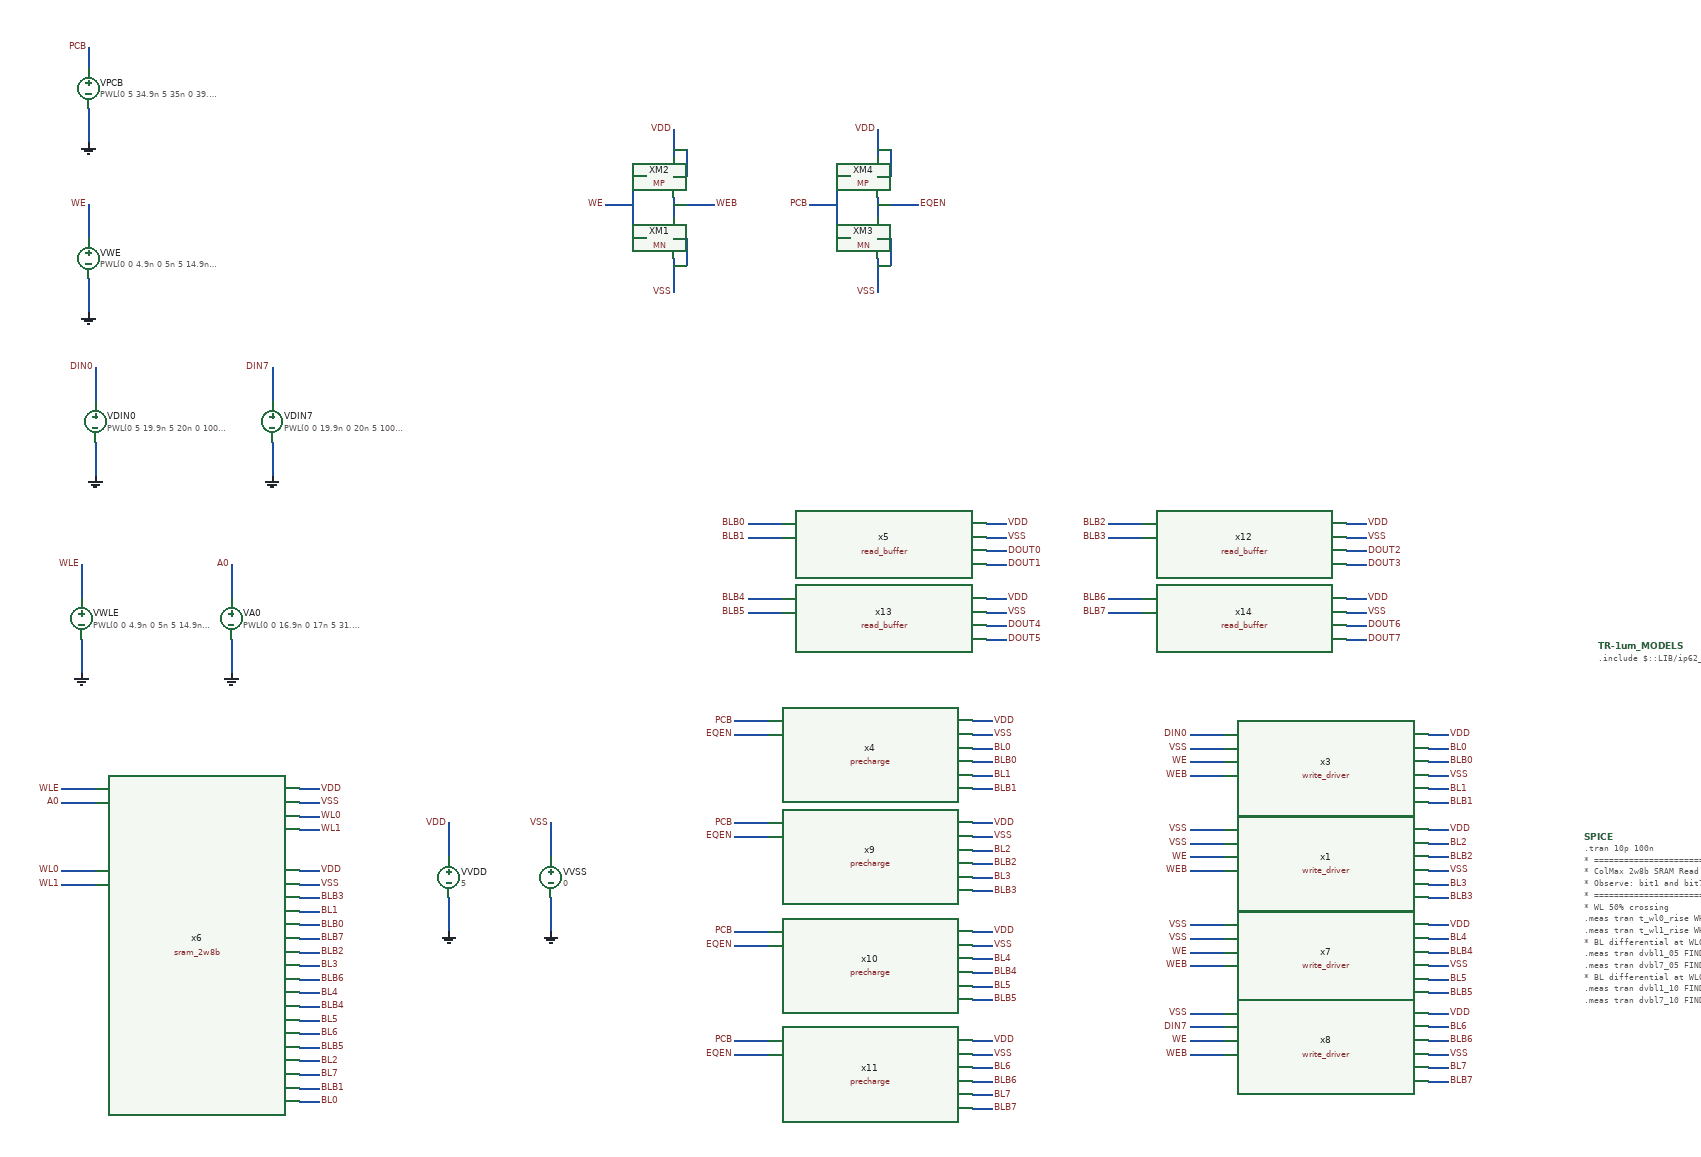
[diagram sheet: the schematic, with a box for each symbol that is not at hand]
v {xschem version=3.4.8RC file_version=1.3}
G {}
K {}
V {}
S {}
F {}
E {}
N 120 -410 170 -410 {lab=WL0}
N 120 -390 170 -390 {lab=WL1}
N 470 -390 500 -390 {lab=VSS}
N 470 -410 500 -410 {lab=VDD}
N 690 -370 690 -320 {lab=0}
N 690 -480 690 -430 {lab=VDD}
N 470 -130 500 -130 {lab=BL2}
N 470 -90 500 -90 {lab=BLB1}
N 470 -330 500 -330 {lab=BLB0}
N 170 -1040 170 -990 {lab=0}
N 170 -1150 170 -1100 {lab=DIN0}
N 840 -370 840 -320 {lab=0}
N 840 -480 840 -430 {lab=VSS}
N 160 -1280 160 -1230 {lab=0}
N 160 -1390 160 -1340 {lab=WE}
N 160 -1620 160 -1590 {lab=PCB}
N 160 -1530 160 -1480 {lab=0}
N 120 -530 170 -530 {lab=WLE}
N 120 -510 170 -510 {lab=A0}
N 470 -530 500 -530 {lab=VDD}
N 470 -510 500 -510 {lab=VSS}
N 470 -490 500 -490 {lab=WL0}
N 470 -470 500 -470 {lab=WL1}
N 150 -750 150 -700 {lab=0}
N 150 -860 150 -810 {lab=WLE}
N 370 -750 370 -700 {lab=0}
N 370 -860 370 -810 {lab=A0}
N 2130 -610 2160 -610 {lab=VDD}
N 2130 -550 2160 -550 {lab=VSS}
N 1780 -570 1830 -570 {lab=WE}
N 1780 -550 1830 -550 {lab=WEB}
N 2130 -590 2160 -590 {lab=BL0}
N 2130 -570 2160 -570 {lab=BLB0}
N 2130 -530 2160 -530 {lab=BL1}
N 2130 -510 2160 -510 {lab=BLB1}
N 1780 -610 1830 -610 {lab=DIN0}
N 1780 -590 1830 -590 {lab=VSS}
N 430 -1040 430 -990 {lab=0}
N 430 -1150 430 -1100 {lab=DIN7}
N 1110 -630 1160 -630 {lab=PCB}
N 1110 -610 1160 -610 {lab=EQEN}
N 1460 -630 1490 -630 {lab=VDD}
N 1460 -610 1490 -610 {lab=VSS}
N 1460 -590 1490 -590 {lab=BL0}
N 1460 -570 1490 -570 {lab=BLB0}
N 1460 -550 1490 -550 {lab=BL1}
N 1460 -530 1490 -530 {lab=BLB1}
N 1480 -920 1510 -920 {lab=VDD}
N 1480 -900 1510 -900 {lab=VSS}
N 1480 -880 1510 -880 {lab=DOUT0}
N 1480 -860 1510 -860 {lab=DOUT1}
N 1130 -920 1180 -920 {lab=BLB0}
N 1130 -900 1180 -900 {lab=BLB1}
N 1020 -1400 1020 -1370 {lab=WEB}
N 1020 -1310 1020 -1260 {lab=VSS}
N 1020 -1340 1040 -1340 {lab=VSS}
N 1040 -1340 1040 -1300 {lab=VSS}
N 1020 -1300 1040 -1300 {lab=VSS}
N 1020 -1500 1020 -1460 {lab=VDD}
N 960 -1430 980 -1430 {lab=WE}
N 960 -1430 960 -1340 {lab=WE}
N 960 -1340 980 -1340 {lab=WE}
N 1020 -1390 1080 -1390 {lab=WEB}
N 920 -1390 960 -1390 {lab=WE}
N 1020 -1430 1040 -1430 {lab=VDD}
N 1040 -1470 1040 -1430 {lab=VDD}
N 1020 -1470 1040 -1470 {lab=VDD}
N 1320 -1400 1320 -1370 {lab=EQEN}
N 1320 -1310 1320 -1260 {lab=VSS}
N 1320 -1340 1340 -1340 {lab=VSS}
N 1340 -1340 1340 -1300 {lab=VSS}
N 1320 -1300 1340 -1300 {lab=VSS}
N 1320 -1500 1320 -1460 {lab=VDD}
N 1260 -1430 1280 -1430 {lab=PCB}
N 1260 -1430 1260 -1340 {lab=PCB}
N 1260 -1340 1280 -1340 {lab=PCB}
N 1320 -1390 1380 -1390 {lab=EQEN}
N 1220 -1390 1260 -1390 {lab=PCB}
N 1320 -1430 1340 -1430 {lab=VDD}
N 1340 -1470 1340 -1430 {lab=VDD}
N 1320 -1470 1340 -1470 {lab=VDD}
N 470 -70 500 -70 {lab=BL0}
N 470 -270 500 -270 {lab=BL3}
N 470 -350 500 -350 {lab=BL1}
N 470 -370 500 -370 {lab=BLB3}
N 470 -230 500 -230 {lab=BL4}
N 470 -210 500 -210 {lab=BLB4}
N 470 -190 500 -190 {lab=BL5}
N 470 -150 500 -150 {lab=BLB5}
N 470 -290 500 -290 {lab=BLB2}
N 470 -250 500 -250 {lab=BLB6}
N 470 -170 500 -170 {lab=BL6}
N 470 -110 500 -110 {lab=BL7}
N 470 -310 500 -310 {lab=BLB7}
N 2130 -470 2160 -470 {lab=VDD}
N 2130 -410 2160 -410 {lab=VSS}
N 1780 -430 1830 -430 {lab=WE}
N 1780 -410 1830 -410 {lab=WEB}
N 2130 -450 2160 -450 {lab=BL2}
N 2130 -430 2160 -430 {lab=BLB2}
N 2130 -390 2160 -390 {lab=BL3}
N 2130 -370 2160 -370 {lab=BLB3}
N 1780 -470 1830 -470 {lab=VSS}
N 1780 -450 1830 -450 {lab=VSS}
N 2130 -330 2160 -330 {lab=VDD}
N 2130 -270 2160 -270 {lab=VSS}
N 1780 -290 1830 -290 {lab=WE}
N 1780 -270 1830 -270 {lab=WEB}
N 2130 -310 2160 -310 {lab=BL4}
N 2130 -290 2160 -290 {lab=BLB4}
N 2130 -250 2160 -250 {lab=BL5}
N 2130 -230 2160 -230 {lab=BLB5}
N 1780 -330 1830 -330 {lab=VSS}
N 1780 -310 1830 -310 {lab=VSS}
N 2130 -200 2160 -200 {lab=VDD}
N 2130 -140 2160 -140 {lab=VSS}
N 1780 -160 1830 -160 {lab=WE}
N 1780 -140 1830 -140 {lab=WEB}
N 2130 -180 2160 -180 {lab=BL6}
N 2130 -160 2160 -160 {lab=BLB6}
N 2130 -120 2160 -120 {lab=BL7}
N 2130 -100 2160 -100 {lab=BLB7}
N 1780 -200 1830 -200 {lab=VSS}
N 1780 -180 1830 -180 {lab=DIN7}
N 1110 -480 1160 -480 {lab=PCB}
N 1110 -460 1160 -460 {lab=EQEN}
N 1460 -480 1490 -480 {lab=VDD}
N 1460 -460 1490 -460 {lab=VSS}
N 1460 -440 1490 -440 {lab=BL2}
N 1460 -420 1490 -420 {lab=BLB2}
N 1460 -400 1490 -400 {lab=BL3}
N 1460 -380 1490 -380 {lab=BLB3}
N 1110 -320 1160 -320 {lab=PCB}
N 1110 -300 1160 -300 {lab=EQEN}
N 1460 -320 1490 -320 {lab=VDD}
N 1460 -300 1490 -300 {lab=VSS}
N 1460 -280 1490 -280 {lab=BL4}
N 1460 -260 1490 -260 {lab=BLB4}
N 1460 -240 1490 -240 {lab=BL5}
N 1460 -220 1490 -220 {lab=BLB5}
N 1110 -160 1160 -160 {lab=PCB}
N 1110 -140 1160 -140 {lab=EQEN}
N 1460 -160 1490 -160 {lab=VDD}
N 1460 -140 1490 -140 {lab=VSS}
N 1460 -120 1490 -120 {lab=BL6}
N 1460 -100 1490 -100 {lab=BLB6}
N 1460 -80 1490 -80 {lab=BL7}
N 1460 -60 1490 -60 {lab=BLB7}
N 2010 -920 2040 -920 {lab=VDD}
N 2010 -900 2040 -900 {lab=VSS}
N 2010 -880 2040 -880 {lab=DOUT2}
N 2010 -860 2040 -860 {lab=DOUT3}
N 1660 -920 1710 -920 {lab=BLB2}
N 1660 -900 1710 -900 {lab=BLB3}
N 1480 -810 1510 -810 {lab=VDD}
N 1480 -790 1510 -790 {lab=VSS}
N 1480 -770 1510 -770 {lab=DOUT4}
N 1480 -750 1510 -750 {lab=DOUT5}
N 1130 -810 1180 -810 {lab=BLB4}
N 1130 -790 1180 -790 {lab=BLB5}
N 2010 -810 2040 -810 {lab=VDD}
N 2010 -790 2040 -790 {lab=VSS}
N 2010 -770 2040 -770 {lab=DOUT6}
N 2010 -750 2040 -750 {lab=DOUT7}
N 1660 -810 1710 -810 {lab=BLB0}
N 1660 -790 1710 -790 {lab=BLB1}
C {devices/lab_pin.sym} 120 -410 0 0 {name=p1 sig_type=std_logic lab=WL0}
C {devices/lab_pin.sym} 120 -390 0 0 {name=p2 sig_type=std_logic lab=WL1}
C {devices/lab_pin.sym} 500 -410 0 1 {name=p3 sig_type=std_logic lab=VDD}
C {devices/vsource.sym} 690 -400 0 0 {name=VVDD value=5 savecurrent=false}
C {devices/gnd.sym} 690 -320 0 0 {name=l4 lab=0}
C {devices/lab_pin.sym} 690 -480 0 0 {name=p6 sig_type=std_logic lab=VDD}
C {devices/lab_pin.sym} 500 -130 0 1 {name=p8 sig_type=std_logic lab=BL2}
C {devices/lab_pin.sym} 500 -90 0 1 {name=p9 sig_type=std_logic lab=BLB1}
C {devices/lab_pin.sym} 500 -330 0 1 {name=p10 sig_type=std_logic lab=BLB0}
C {devices/vsource.sym} 170 -1070 0 0 {name=VDIN0 value="PWL(0 5 19.9n 5 20n 0 100n 0)" savecurrent=false}
C {devices/gnd.sym} 170 -990 0 0 {name=l5 lab=0}
C {devices/lab_pin.sym} 170 -1150 0 0 {name=p35 sig_type=std_logic lab=DIN0}
C {devices/vsource.sym} 840 -400 0 0 {name=VVSS value=0 savecurrent=false}
C {devices/gnd.sym} 840 -320 0 0 {name=l9 lab=0}
C {devices/lab_pin.sym} 840 -480 0 0 {name=p43 sig_type=std_logic lab=VSS}
C {devices/lab_pin.sym} 500 -390 0 1 {name=p39 sig_type=std_logic lab=VSS}
C {devices/vsource.sym} 160 -1310 0 0 {name=VWE value="PWL(0 0 4.9n 0 5n 5 14.9n 5 15n 0 19.9n 0 20n 5 29.9n 5 30n 0 100n 0)" savecurrent=false}
C {devices/gnd.sym} 160 -1230 0 0 {name=l1 lab=0}
C {devices/lab_pin.sym} 160 -1390 0 0 {name=p40 sig_type=std_logic lab=WE}
C {devices/code.sym} 2380 -740 0 0 {name=TR-1um_MODELS
only_toplevel=true
format="tcleval( @value )"
value=".include $::LIB/ip62_models"
spice_ignore=false}
C {devices/code_shown.sym} 2360 -460 0 0 {name=SPICE only_toplevel=false value="
.tran 10p 100n

* ============================================================
* ColMax 2w8b SRAM Read Measurement
* Observe: bit1 and bit7
* ============================================================

* WL 50% crossing
.meas tran t_wl0_rise WHEN v(WL0)=2.5 RISE=2
.meas tran t_wl1_rise WHEN v(WL1)=2.5 RISE=1

* BL differential at WL0 +0.5ns
.meas tran dvbl1_05 FIND par('abs(v(BL1)-v(BLB1))') AT=47.781n
.meas tran dvbl7_05 FIND par('abs(v(BL7)-v(BLB7))') AT=47.781n

* BL differential at WL0 +1.0ns
.meas tran dvbl1_10 FIND par('abs(v(BL1)-v(BLB1))') AT=48.281n
.meas tran dvbl7_10 FIND par('abs(v(BL7)-v(BLB7))') AT=48.281n

* Time when BL differential reaches 1.0V
.meas tran t_dvbl1_1v WHEN par('abs(v(BL1)-v(BLB1))')=1.0 RISE=1 TD=47n
.meas tran t_dvbl7_1v WHEN par('abs(v(BL7)-v(BLB7))')=1.0 RISE=1 TD=47n

* Delay from WL0 50% to 1.0V BL differential
.meas tran td_bl1 PARAM='t_dvbl1_1v-t_wl0_rise'
.meas tran td_bl7 PARAM='t_dvbl7_1v-t_wl0_rise'

.control
run

plot v(pcb) v(eqen)+6
plot v(wl0) v(wl1)+6
plot v(dout1) v(dout7)+6
plot v(bl1) v(blb1)
plot v(bl7) v(blb7)

.endc
"}
C {devices/vsource.sym} 160 -1560 0 0 {name=VPCB value="PWL(0 5 34.9n 5 35n 0 39.9n 0 40n 5 59.9n 5 60n 0 64.9n 0 65n 5 100n 5)" savecurrent=false}
C {devices/lab_pin.sym} 160 -1620 0 0 {name=p65 sig_type=std_logic lab=PCB}
C {devices/gnd.sym} 160 -1480 0 0 {name=l13 lab=0}
C {decoder.sym} 320 -500 0 0 {name=x2}
C {devices/lab_pin.sym} 120 -530 0 0 {name=p4 sig_type=std_logic lab=WLE}
C {devices/lab_pin.sym} 120 -510 0 0 {name=p5 sig_type=std_logic lab=A0}
C {devices/lab_pin.sym} 500 -530 0 1 {name=p67 sig_type=std_logic lab=VDD}
C {devices/lab_pin.sym} 500 -510 0 1 {name=p68 sig_type=std_logic lab=VSS}
C {devices/lab_pin.sym} 500 -490 0 1 {name=p69 sig_type=std_logic lab=WL0}
C {devices/lab_pin.sym} 500 -470 0 1 {name=p70 sig_type=std_logic lab=WL1}
C {devices/vsource.sym} 150 -780 0 0 {name=VWLE value="PWL(0 0 4.9n 0 5n 5 14.9n 5 15n 0 19.9n 0 20n 5 29.9n 5 30n 0 44.9n 0 45n 5 54.9n 5 55n 0 69.9n 0 70n 5 79.9n 5 80n 0 100n 0)" savecurrent=false}
C {devices/gnd.sym} 150 -700 0 0 {name=l2 lab=0
value=1}
C {devices/lab_pin.sym} 150 -860 0 0 {name=p71 sig_type=std_logic lab=WLE}
C {devices/vsource.sym} 370 -780 0 0 {name=VA0 value="PWL(0 0 16.9n 0 17n 5 31.9n 5 32n 0 56.9n 0 57n 5 100n 5)" savecurrent=false}
C {devices/gnd.sym} 370 -700 0 0 {name=l3 lab=0
value=1}
C {devices/lab_pin.sym} 370 -860 0 0 {name=p72 sig_type=std_logic lab=A0}
C {write_driver.sym} 1980 -560 0 0 {name=x3}
C {devices/lab_pin.sym} 2160 -610 0 1 {name=p11 sig_type=std_logic lab=VDD}
C {devices/lab_pin.sym} 2160 -550 0 1 {name=p12 sig_type=std_logic lab=VSS}
C {devices/lab_pin.sym} 1780 -570 0 0 {name=p13 sig_type=std_logic lab=WE}
C {devices/lab_pin.sym} 1780 -550 0 0 {name=p14 sig_type=std_logic lab=WEB}
C {devices/lab_pin.sym} 2160 -590 0 1 {name=p15 sig_type=std_logic lab=BL0}
C {devices/lab_pin.sym} 2160 -570 0 1 {name=p16 sig_type=std_logic lab=BLB0}
C {devices/lab_pin.sym} 2160 -530 0 1 {name=p17 sig_type=std_logic lab=BL1}
C {devices/lab_pin.sym} 2160 -510 0 1 {name=p18 sig_type=std_logic lab=BLB1}
C {devices/lab_pin.sym} 1780 -610 0 0 {name=p19 sig_type=std_logic lab=DIN0}
C {devices/lab_pin.sym} 1780 -590 0 0 {name=p20 sig_type=std_logic lab=VSS}
C {devices/vsource.sym} 430 -1070 0 0 {name=VDIN7 value="PWL(0 0 19.9n 0 20n 5 100n 5)" savecurrent=false}
C {devices/gnd.sym} 430 -990 0 0 {name=l6 lab=0}
C {devices/lab_pin.sym} 430 -1150 0 0 {name=p21 sig_type=std_logic lab=DIN7}
C {precharge.sym} 1310 -580 0 0 {name=x4}
C {devices/lab_pin.sym} 1110 -630 0 0 {name=p22 sig_type=std_logic lab=PCB}
C {devices/lab_pin.sym} 1110 -610 0 0 {name=p23 sig_type=std_logic lab=EQEN}
C {devices/lab_pin.sym} 1490 -630 0 1 {name=p24 sig_type=std_logic lab=VDD}
C {devices/lab_pin.sym} 1490 -610 0 1 {name=p25 sig_type=std_logic lab=VSS}
C {devices/lab_pin.sym} 1490 -590 0 1 {name=p26 sig_type=std_logic lab=BL0}
C {devices/lab_pin.sym} 1490 -570 0 1 {name=p27 sig_type=std_logic lab=BLB0}
C {devices/lab_pin.sym} 1490 -550 0 1 {name=p28 sig_type=std_logic lab=BL1}
C {devices/lab_pin.sym} 1490 -530 0 1 {name=p29 sig_type=std_logic lab=BLB1}
C {read_buffer.sym} 1330 -890 0 0 {name=x5}
C {devices/lab_pin.sym} 1510 -920 0 1 {name=p30 sig_type=std_logic lab=VDD}
C {devices/lab_pin.sym} 1510 -900 0 1 {name=p31 sig_type=std_logic lab=VSS}
C {devices/lab_pin.sym} 1510 -880 0 1 {name=p32 sig_type=std_logic lab=DOUT0}
C {devices/lab_pin.sym} 1510 -860 0 1 {name=p33 sig_type=std_logic lab=DOUT1}
C {devices/lab_pin.sym} 1130 -920 0 0 {name=p34 sig_type=std_logic lab=BLB0}
C {devices/lab_pin.sym} 1130 -900 0 0 {name=p36 sig_type=std_logic lab=BLB1}
C {devices/lab_pin.sym} 1020 -1500 0 0 {name=p63 sig_type=std_logic lab=VDD}
C {devices/lab_pin.sym} 920 -1390 0 0 {name=p64 sig_type=std_logic lab=WE}
C {devices/lab_pin.sym} 1080 -1390 0 1 {name=p41 sig_type=std_logic lab=WEB}
C {devices/lab_pin.sym} 1020 -1260 0 0 {name=p45 sig_type=std_logic lab=VSS}
C {TR-1umLIB/MN.sym} 980 -1340 0 0 {name=XM1
model=NMOS
w=3.4u
l=1u
m=1
spiceprefix=X
as=0
ad=0
ps=0
pd=0
nrd=0
nrs=0}
C {TR-1umLIB/MP.sym} 980 -1430 0 0 {name=XM2
model=PMOS
w=6.8u
l=1u
m=1
spiceprefix=X
as=0
ad=0
ps=0
pd=0
nrd=0
nrs=0}
C {devices/lab_pin.sym} 1320 -1500 0 0 {name=p46 sig_type=std_logic lab=VDD}
C {devices/lab_pin.sym} 1220 -1390 0 0 {name=p47 sig_type=std_logic lab=PCB}
C {devices/lab_pin.sym} 1380 -1390 0 1 {name=p48 sig_type=std_logic lab=EQEN}
C {devices/lab_pin.sym} 1320 -1260 0 0 {name=p49 sig_type=std_logic lab=VSS}
C {TR-1umLIB/MN.sym} 1280 -1340 0 0 {name=XM3
model=NMOS
w=3.4u
l=1u
m=1
spiceprefix=X
as=0
ad=0
ps=0
pd=0
nrd=0
nrs=0}
C {TR-1umLIB/MP.sym} 1280 -1430 0 0 {name=XM4
model=PMOS
w=6.8u
l=1u
m=1
spiceprefix=X
as=0
ad=0
ps=0
pd=0
nrd=0
nrs=0}
C {sram_2w8b.sym} 320 -240 0 0 {name=x6}
C {devices/lab_pin.sym} 500 -70 0 1 {name=p37 sig_type=std_logic lab=BL0}
C {devices/lab_pin.sym} 500 -270 0 1 {name=p7 sig_type=std_logic lab=BL3}
C {devices/lab_pin.sym} 500 -350 0 1 {name=p38 sig_type=std_logic lab=BL1}
C {devices/lab_pin.sym} 500 -370 0 1 {name=p42 sig_type=std_logic lab=BLB3}
C {devices/lab_pin.sym} 500 -230 0 1 {name=p44 sig_type=std_logic lab=BL4}
C {devices/lab_pin.sym} 500 -210 0 1 {name=p50 sig_type=std_logic lab=BLB4}
C {devices/lab_pin.sym} 500 -190 0 1 {name=p51 sig_type=std_logic lab=BL5}
C {devices/lab_pin.sym} 500 -150 0 1 {name=p52 sig_type=std_logic lab=BLB5}
C {devices/lab_pin.sym} 500 -290 0 1 {name=p53 sig_type=std_logic lab=BLB2}
C {devices/lab_pin.sym} 500 -250 0 1 {name=p54 sig_type=std_logic lab=BLB6}
C {devices/lab_pin.sym} 500 -170 0 1 {name=p55 sig_type=std_logic lab=BL6}
C {devices/lab_pin.sym} 500 -110 0 1 {name=p56 sig_type=std_logic lab=BL7}
C {devices/lab_pin.sym} 500 -310 0 1 {name=p57 sig_type=std_logic lab=BLB7}
C {write_driver.sym} 1980 -420 0 0 {name=x1}
C {devices/lab_pin.sym} 2160 -470 0 1 {name=p58 sig_type=std_logic lab=VDD}
C {devices/lab_pin.sym} 2160 -410 0 1 {name=p59 sig_type=std_logic lab=VSS}
C {devices/lab_pin.sym} 1780 -430 0 0 {name=p60 sig_type=std_logic lab=WE}
C {devices/lab_pin.sym} 1780 -410 0 0 {name=p61 sig_type=std_logic lab=WEB}
C {devices/lab_pin.sym} 2160 -450 0 1 {name=p62 sig_type=std_logic lab=BL2}
C {devices/lab_pin.sym} 2160 -430 0 1 {name=p66 sig_type=std_logic lab=BLB2}
C {devices/lab_pin.sym} 2160 -390 0 1 {name=p73 sig_type=std_logic lab=BL3}
C {devices/lab_pin.sym} 2160 -370 0 1 {name=p74 sig_type=std_logic lab=BLB3}
C {devices/lab_pin.sym} 1780 -470 0 0 {name=p75 sig_type=std_logic lab=VSS}
C {devices/lab_pin.sym} 1780 -450 0 0 {name=p76 sig_type=std_logic lab=VSS}
C {write_driver.sym} 1980 -280 0 0 {name=x7}
C {devices/lab_pin.sym} 2160 -330 0 1 {name=p77 sig_type=std_logic lab=VDD}
C {devices/lab_pin.sym} 2160 -270 0 1 {name=p78 sig_type=std_logic lab=VSS}
C {devices/lab_pin.sym} 1780 -290 0 0 {name=p79 sig_type=std_logic lab=WE}
C {devices/lab_pin.sym} 1780 -270 0 0 {name=p80 sig_type=std_logic lab=WEB}
C {devices/lab_pin.sym} 2160 -310 0 1 {name=p81 sig_type=std_logic lab=BL4}
C {devices/lab_pin.sym} 2160 -290 0 1 {name=p82 sig_type=std_logic lab=BLB4}
C {devices/lab_pin.sym} 2160 -250 0 1 {name=p83 sig_type=std_logic lab=BL5}
C {devices/lab_pin.sym} 2160 -230 0 1 {name=p84 sig_type=std_logic lab=BLB5}
C {devices/lab_pin.sym} 1780 -330 0 0 {name=p85 sig_type=std_logic lab=VSS}
C {devices/lab_pin.sym} 1780 -310 0 0 {name=p86 sig_type=std_logic lab=VSS}
C {write_driver.sym} 1980 -150 0 0 {name=x8}
C {devices/lab_pin.sym} 2160 -200 0 1 {name=p87 sig_type=std_logic lab=VDD}
C {devices/lab_pin.sym} 2160 -140 0 1 {name=p88 sig_type=std_logic lab=VSS}
C {devices/lab_pin.sym} 1780 -160 0 0 {name=p89 sig_type=std_logic lab=WE}
C {devices/lab_pin.sym} 1780 -140 0 0 {name=p90 sig_type=std_logic lab=WEB}
C {devices/lab_pin.sym} 2160 -180 0 1 {name=p91 sig_type=std_logic lab=BL6}
C {devices/lab_pin.sym} 2160 -160 0 1 {name=p92 sig_type=std_logic lab=BLB6}
C {devices/lab_pin.sym} 2160 -120 0 1 {name=p93 sig_type=std_logic lab=BL7}
C {devices/lab_pin.sym} 2160 -100 0 1 {name=p94 sig_type=std_logic lab=BLB7}
C {devices/lab_pin.sym} 1780 -200 0 0 {name=p95 sig_type=std_logic lab=VSS}
C {devices/lab_pin.sym} 1780 -180 0 0 {name=p96 sig_type=std_logic lab=DIN7}
C {precharge.sym} 1310 -430 0 0 {name=x9}
C {devices/lab_pin.sym} 1110 -480 0 0 {name=p97 sig_type=std_logic lab=PCB}
C {devices/lab_pin.sym} 1110 -460 0 0 {name=p98 sig_type=std_logic lab=EQEN}
C {devices/lab_pin.sym} 1490 -480 0 1 {name=p99 sig_type=std_logic lab=VDD}
C {devices/lab_pin.sym} 1490 -460 0 1 {name=p100 sig_type=std_logic lab=VSS}
C {devices/lab_pin.sym} 1490 -440 0 1 {name=p101 sig_type=std_logic lab=BL2}
C {devices/lab_pin.sym} 1490 -420 0 1 {name=p102 sig_type=std_logic lab=BLB2}
C {devices/lab_pin.sym} 1490 -400 0 1 {name=p103 sig_type=std_logic lab=BL3}
C {devices/lab_pin.sym} 1490 -380 0 1 {name=p104 sig_type=std_logic lab=BLB3}
C {precharge.sym} 1310 -270 0 0 {name=x10}
C {devices/lab_pin.sym} 1110 -320 0 0 {name=p105 sig_type=std_logic lab=PCB}
C {devices/lab_pin.sym} 1110 -300 0 0 {name=p106 sig_type=std_logic lab=EQEN}
C {devices/lab_pin.sym} 1490 -320 0 1 {name=p107 sig_type=std_logic lab=VDD}
C {devices/lab_pin.sym} 1490 -300 0 1 {name=p108 sig_type=std_logic lab=VSS}
C {devices/lab_pin.sym} 1490 -280 0 1 {name=p109 sig_type=std_logic lab=BL4}
C {devices/lab_pin.sym} 1490 -260 0 1 {name=p110 sig_type=std_logic lab=BLB4}
C {devices/lab_pin.sym} 1490 -240 0 1 {name=p111 sig_type=std_logic lab=BL5}
C {devices/lab_pin.sym} 1490 -220 0 1 {name=p112 sig_type=std_logic lab=BLB5}
C {precharge.sym} 1310 -110 0 0 {name=x11}
C {devices/lab_pin.sym} 1110 -160 0 0 {name=p113 sig_type=std_logic lab=PCB}
C {devices/lab_pin.sym} 1110 -140 0 0 {name=p114 sig_type=std_logic lab=EQEN}
C {devices/lab_pin.sym} 1490 -160 0 1 {name=p115 sig_type=std_logic lab=VDD}
C {devices/lab_pin.sym} 1490 -140 0 1 {name=p116 sig_type=std_logic lab=VSS}
C {devices/lab_pin.sym} 1490 -120 0 1 {name=p117 sig_type=std_logic lab=BL6}
C {devices/lab_pin.sym} 1490 -100 0 1 {name=p118 sig_type=std_logic lab=BLB6}
C {devices/lab_pin.sym} 1490 -80 0 1 {name=p119 sig_type=std_logic lab=BL7}
C {devices/lab_pin.sym} 1490 -60 0 1 {name=p120 sig_type=std_logic lab=BLB7}
C {read_buffer.sym} 1860 -890 0 0 {name=x12}
C {devices/lab_pin.sym} 2040 -920 0 1 {name=p121 sig_type=std_logic lab=VDD}
C {devices/lab_pin.sym} 2040 -900 0 1 {name=p122 sig_type=std_logic lab=VSS}
C {devices/lab_pin.sym} 2040 -880 0 1 {name=p123 sig_type=std_logic lab=DOUT2}
C {devices/lab_pin.sym} 2040 -860 0 1 {name=p124 sig_type=std_logic lab=DOUT3}
C {devices/lab_pin.sym} 1660 -920 0 0 {name=p125 sig_type=std_logic lab=BLB2}
C {devices/lab_pin.sym} 1660 -900 0 0 {name=p126 sig_type=std_logic lab=BLB3}
C {read_buffer.sym} 1330 -780 0 0 {name=x13}
C {devices/lab_pin.sym} 1510 -810 0 1 {name=p127 sig_type=std_logic lab=VDD}
C {devices/lab_pin.sym} 1510 -790 0 1 {name=p128 sig_type=std_logic lab=VSS}
C {devices/lab_pin.sym} 1510 -770 0 1 {name=p129 sig_type=std_logic lab=DOUT4}
C {devices/lab_pin.sym} 1510 -750 0 1 {name=p130 sig_type=std_logic lab=DOUT5}
C {devices/lab_pin.sym} 1130 -810 0 0 {name=p131 sig_type=std_logic lab=BLB4}
C {devices/lab_pin.sym} 1130 -790 0 0 {name=p132 sig_type=std_logic lab=BLB5}
C {read_buffer.sym} 1860 -780 0 0 {name=x14}
C {devices/lab_pin.sym} 2040 -810 0 1 {name=p133 sig_type=std_logic lab=VDD}
C {devices/lab_pin.sym} 2040 -790 0 1 {name=p134 sig_type=std_logic lab=VSS}
C {devices/lab_pin.sym} 2040 -770 0 1 {name=p135 sig_type=std_logic lab=DOUT6}
C {devices/lab_pin.sym} 2040 -750 0 1 {name=p136 sig_type=std_logic lab=DOUT7}
C {devices/lab_pin.sym} 1660 -810 0 0 {name=p137 sig_type=std_logic lab=BLB6}
C {devices/lab_pin.sym} 1660 -790 0 0 {name=p138 sig_type=std_logic lab=BLB7}
